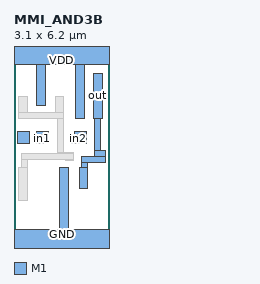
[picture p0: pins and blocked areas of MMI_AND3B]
MACRO MMI_AND3B
	CLASS CORE ;
	FOREIGN MMI_AND3B 0 0 ;
	SIZE 3.1 BY 6.2 ;
	SYMMETRY X Y ;
	SITE CORE1 ;
	PIN out
		DIRECTION output ;
		USE SIGNAL ;
		PORT
			LAYER M1 ;
			RECT 2.595 4.04 2.875 5.51 ;
			LAYER M1 ;
			RECT 2.635 2.98 2.825 4.04 ;
			LAYER M1 ;
			RECT 2.635 2.795 2.98 2.98 ;
			LAYER M1 ;
			RECT 2.215 2.6 2.98 2.795 ;
			LAYER M1 ;
			RECT 2.215 2.445 2.405 2.6 ;
			LAYER M1 ;
			RECT 2.125 1.745 2.405 2.445 ;
		END
		AntennaDiffArea 0.91245 ;
	END out
	PIN in1
		DIRECTION input ;
		USE SIGNAL ;
		PORT
			LAYER M1 ;
			RECT 0.74 3.51 1.12 3.6 ;
			LAYER M1 ;
			RECT 0.725 3.23 1.12 3.51 ;
			LAYER M1 ;
			RECT 0.74 3.22 1.12 3.23 ;
		END
		AntennaGateArea 0.28875 ;
	END in1
	PIN GND
		DIRECTION inout ;
		USE GROUND ;
		PORT
			LAYER M1 ;
			RECT 1.49 0.42 1.77 2.445 ;
			LAYER M1 ;
			RECT 0 -0.42 3.1 0.42 ;
		END
	END GND
	PIN in2
		DIRECTION input ;
		USE SIGNAL ;
		PORT
			LAYER M1 ;
			RECT 1.98 3.51 2.36 3.6 ;
			LAYER M1 ;
			RECT 1.83 3.23 2.36 3.51 ;
			LAYER M1 ;
			RECT 1.98 3.22 2.36 3.23 ;
		END
		AntennaGateArea 0.28875 ;
	END in2
	PIN VDD
		DIRECTION inout ;
		USE POWER ;
		PORT
			LAYER M1 ;
			RECT 0 5.78 3.1 6.62 ;
			LAYER M1 ;
			RECT 0.75 4.46 1.03 5.78 ;
			LAYER M1 ;
			RECT 2.005 4.04 2.285 5.78 ;
		END
	END VDD
	PIN in0
		DIRECTION input ;
		USE SIGNAL ;
		PORT
			LAYER M1 ;
			RECT 0.12 3.22 0.5 3.6 ;
		END
		AntennaGateArea 0.28875 ;
	END in0
	OBS
		LAYER M1 ;
		RECT 0.16 4.23 0.44 4.74 ;
		LAYER M1 ;
		RECT 1.34 4.23 1.62 4.74 ;
		LAYER M1 ;
		RECT 0.15 4.04 1.62 4.23 ;
		LAYER M1 ;
		RECT 1.42 2.93 1.61 4.04 ;
		LAYER M1 ;
		RECT 1.42 2.885 1.945 2.93 ;
		LAYER M1 ;
		RECT 0.245 2.695 1.945 2.885 ;
		LAYER M1 ;
		RECT 0.245 2.445 0.435 2.695 ;
		LAYER M1 ;
		RECT 1.665 2.65 1.945 2.695 ;
		LAYER M1 ;
		RECT 0.16 1.36 0.44 2.445 ;
	END
END MMI_AND3B
